VERSION 5.7 ;
BUSBITCHARS "[]" ;
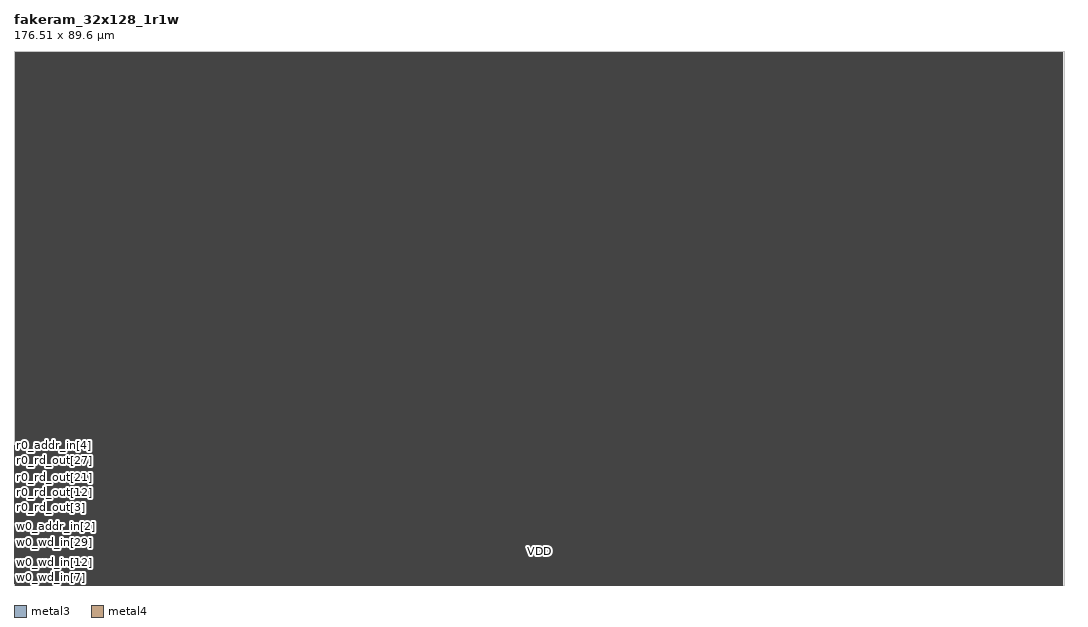
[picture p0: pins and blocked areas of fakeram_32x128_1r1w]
MACRO fakeram_32x128_1r1w
  FOREIGN fakeram_32x128_1r1w 0 0 ;
  SYMMETRY X Y R90 ;
  SIZE 176.510 BY 89.600 ;
  CLASS BLOCK ;
  PIN w0_wd_in[0]
    DIRECTION INPUT ;
    USE SIGNAL ;
    SHAPE ABUTMENT ;
    PORT
      LAYER metal3 ;
      RECT 0.000 0.280 0.140 0.420 ;
    END
  END w0_wd_in[0]
  PIN w0_wd_in[1]
    DIRECTION INPUT ;
    USE SIGNAL ;
    SHAPE ABUTMENT ;
    PORT
      LAYER metal3 ;
      RECT 0.000 0.560 0.140 0.700 ;
    END
  END w0_wd_in[1]
  PIN w0_wd_in[2]
    DIRECTION INPUT ;
    USE SIGNAL ;
    SHAPE ABUTMENT ;
    PORT
      LAYER metal3 ;
      RECT 0.000 0.840 0.140 0.980 ;
    END
  END w0_wd_in[2]
  PIN w0_wd_in[3]
    DIRECTION INPUT ;
    USE SIGNAL ;
    SHAPE ABUTMENT ;
    PORT
      LAYER metal3 ;
      RECT 0.000 1.120 0.140 1.260 ;
    END
  END w0_wd_in[3]
  PIN w0_wd_in[4]
    DIRECTION INPUT ;
    USE SIGNAL ;
    SHAPE ABUTMENT ;
    PORT
      LAYER metal3 ;
      RECT 0.000 1.400 0.140 1.540 ;
    END
  END w0_wd_in[4]
  PIN w0_wd_in[5]
    DIRECTION INPUT ;
    USE SIGNAL ;
    SHAPE ABUTMENT ;
    PORT
      LAYER metal3 ;
      RECT 0.000 1.680 0.140 1.820 ;
    END
  END w0_wd_in[5]
  PIN w0_wd_in[6]
    DIRECTION INPUT ;
    USE SIGNAL ;
    SHAPE ABUTMENT ;
    PORT
      LAYER metal3 ;
      RECT 0.000 1.960 0.140 2.100 ;
    END
  END w0_wd_in[6]
  PIN w0_wd_in[7]
    DIRECTION INPUT ;
    USE SIGNAL ;
    SHAPE ABUTMENT ;
    PORT
      LAYER metal3 ;
      RECT 0.000 2.240 0.140 2.380 ;
    END
  END w0_wd_in[7]
  PIN w0_wd_in[8]
    DIRECTION INPUT ;
    USE SIGNAL ;
    SHAPE ABUTMENT ;
    PORT
      LAYER metal3 ;
      RECT 0.000 2.520 0.140 2.660 ;
    END
  END w0_wd_in[8]
  PIN w0_wd_in[9]
    DIRECTION INPUT ;
    USE SIGNAL ;
    SHAPE ABUTMENT ;
    PORT
      LAYER metal3 ;
      RECT 0.000 2.800 0.140 2.940 ;
    END
  END w0_wd_in[9]
  PIN w0_wd_in[10]
    DIRECTION INPUT ;
    USE SIGNAL ;
    SHAPE ABUTMENT ;
    PORT
      LAYER metal3 ;
      RECT 0.000 3.080 0.140 3.220 ;
    END
  END w0_wd_in[10]
  PIN w0_wd_in[11]
    DIRECTION INPUT ;
    USE SIGNAL ;
    SHAPE ABUTMENT ;
    PORT
      LAYER metal3 ;
      RECT 0.000 3.360 0.140 3.500 ;
    END
  END w0_wd_in[11]
  PIN w0_wd_in[12]
    DIRECTION INPUT ;
    USE SIGNAL ;
    SHAPE ABUTMENT ;
    PORT
      LAYER metal3 ;
      RECT 0.000 3.640 0.140 3.780 ;
    END
  END w0_wd_in[12]
  PIN w0_wd_in[13]
    DIRECTION INPUT ;
    USE SIGNAL ;
    SHAPE ABUTMENT ;
    PORT
      LAYER metal3 ;
      RECT 0.000 3.920 0.140 4.060 ;
    END
  END w0_wd_in[13]
  PIN w0_wd_in[14]
    DIRECTION INPUT ;
    USE SIGNAL ;
    SHAPE ABUTMENT ;
    PORT
      LAYER metal3 ;
      RECT 0.000 4.200 0.140 4.340 ;
    END
  END w0_wd_in[14]
  PIN w0_wd_in[15]
    DIRECTION INPUT ;
    USE SIGNAL ;
    SHAPE ABUTMENT ;
    PORT
      LAYER metal3 ;
      RECT 0.000 4.480 0.140 4.620 ;
    END
  END w0_wd_in[15]
  PIN w0_wd_in[16]
    DIRECTION INPUT ;
    USE SIGNAL ;
    SHAPE ABUTMENT ;
    PORT
      LAYER metal3 ;
      RECT 0.000 4.760 0.140 4.900 ;
    END
  END w0_wd_in[16]
  PIN w0_wd_in[17]
    DIRECTION INPUT ;
    USE SIGNAL ;
    SHAPE ABUTMENT ;
    PORT
      LAYER metal3 ;
      RECT 0.000 5.040 0.140 5.180 ;
    END
  END w0_wd_in[17]
  PIN w0_wd_in[18]
    DIRECTION INPUT ;
    USE SIGNAL ;
    SHAPE ABUTMENT ;
    PORT
      LAYER metal3 ;
      RECT 0.000 5.320 0.140 5.460 ;
    END
  END w0_wd_in[18]
  PIN w0_wd_in[19]
    DIRECTION INPUT ;
    USE SIGNAL ;
    SHAPE ABUTMENT ;
    PORT
      LAYER metal3 ;
      RECT 0.000 5.600 0.140 5.740 ;
    END
  END w0_wd_in[19]
  PIN w0_wd_in[20]
    DIRECTION INPUT ;
    USE SIGNAL ;
    SHAPE ABUTMENT ;
    PORT
      LAYER metal3 ;
      RECT 0.000 5.880 0.140 6.020 ;
    END
  END w0_wd_in[20]
  PIN w0_wd_in[21]
    DIRECTION INPUT ;
    USE SIGNAL ;
    SHAPE ABUTMENT ;
    PORT
      LAYER metal3 ;
      RECT 0.000 6.160 0.140 6.300 ;
    END
  END w0_wd_in[21]
  PIN w0_wd_in[22]
    DIRECTION INPUT ;
    USE SIGNAL ;
    SHAPE ABUTMENT ;
    PORT
      LAYER metal3 ;
      RECT 0.000 6.440 0.140 6.580 ;
    END
  END w0_wd_in[22]
  PIN w0_wd_in[23]
    DIRECTION INPUT ;
    USE SIGNAL ;
    SHAPE ABUTMENT ;
    PORT
      LAYER metal3 ;
      RECT 0.000 6.720 0.140 6.860 ;
    END
  END w0_wd_in[23]
  PIN w0_wd_in[24]
    DIRECTION INPUT ;
    USE SIGNAL ;
    SHAPE ABUTMENT ;
    PORT
      LAYER metal3 ;
      RECT 0.000 7.000 0.140 7.140 ;
    END
  END w0_wd_in[24]
  PIN w0_wd_in[25]
    DIRECTION INPUT ;
    USE SIGNAL ;
    SHAPE ABUTMENT ;
    PORT
      LAYER metal3 ;
      RECT 0.000 7.280 0.140 7.420 ;
    END
  END w0_wd_in[25]
  PIN w0_wd_in[26]
    DIRECTION INPUT ;
    USE SIGNAL ;
    SHAPE ABUTMENT ;
    PORT
      LAYER metal3 ;
      RECT 0.000 7.560 0.140 7.700 ;
    END
  END w0_wd_in[26]
  PIN w0_wd_in[27]
    DIRECTION INPUT ;
    USE SIGNAL ;
    SHAPE ABUTMENT ;
    PORT
      LAYER metal3 ;
      RECT 0.000 7.840 0.140 7.980 ;
    END
  END w0_wd_in[27]
  PIN w0_wd_in[28]
    DIRECTION INPUT ;
    USE SIGNAL ;
    SHAPE ABUTMENT ;
    PORT
      LAYER metal3 ;
      RECT 0.000 8.120 0.140 8.260 ;
    END
  END w0_wd_in[28]
  PIN w0_wd_in[29]
    DIRECTION INPUT ;
    USE SIGNAL ;
    SHAPE ABUTMENT ;
    PORT
      LAYER metal3 ;
      RECT 0.000 8.400 0.140 8.540 ;
    END
  END w0_wd_in[29]
  PIN w0_wd_in[30]
    DIRECTION INPUT ;
    USE SIGNAL ;
    SHAPE ABUTMENT ;
    PORT
      LAYER metal3 ;
      RECT 0.000 8.680 0.140 8.820 ;
    END
  END w0_wd_in[30]
  PIN w0_wd_in[31]
    DIRECTION INPUT ;
    USE SIGNAL ;
    SHAPE ABUTMENT ;
    PORT
      LAYER metal3 ;
      RECT 0.000 8.960 0.140 9.100 ;
    END
  END w0_wd_in[31]
  PIN w0_addr_in[0]
    DIRECTION INPUT ;
    USE SIGNAL ;
    SHAPE ABUTMENT ;
    PORT
      LAYER metal3 ;
      RECT 0.000 9.240 0.140 9.380 ;
    END
  END w0_addr_in[0]
  PIN w0_addr_in[1]
    DIRECTION INPUT ;
    USE SIGNAL ;
    SHAPE ABUTMENT ;
    PORT
      LAYER metal3 ;
      RECT 0.000 9.520 0.140 9.660 ;
    END
  END w0_addr_in[1]
  PIN w0_addr_in[2]
    DIRECTION INPUT ;
    USE SIGNAL ;
    SHAPE ABUTMENT ;
    PORT
      LAYER metal3 ;
      RECT 0.000 9.800 0.140 9.940 ;
    END
  END w0_addr_in[2]
  PIN w0_addr_in[3]
    DIRECTION INPUT ;
    USE SIGNAL ;
    SHAPE ABUTMENT ;
    PORT
      LAYER metal3 ;
      RECT 0.000 10.080 0.140 10.220 ;
    END
  END w0_addr_in[3]
  PIN w0_addr_in[4]
    DIRECTION INPUT ;
    USE SIGNAL ;
    SHAPE ABUTMENT ;
    PORT
      LAYER metal3 ;
      RECT 0.000 10.360 0.140 10.500 ;
    END
  END w0_addr_in[4]
  PIN w0_addr_in[5]
    DIRECTION INPUT ;
    USE SIGNAL ;
    SHAPE ABUTMENT ;
    PORT
      LAYER metal3 ;
      RECT 0.000 10.640 0.140 10.780 ;
    END
  END w0_addr_in[5]
  PIN w0_addr_in[6]
    DIRECTION INPUT ;
    USE SIGNAL ;
    SHAPE ABUTMENT ;
    PORT
      LAYER metal3 ;
      RECT 0.000 10.920 0.140 11.060 ;
    END
  END w0_addr_in[6]
  PIN w0_clk
    DIRECTION INPUT ;
    USE SIGNAL ;
    SHAPE ABUTMENT ;
    PORT
      LAYER metal3 ;
      RECT 0.000 11.200 0.140 11.340 ;
    END
  END w0_clk
  PIN w0_ce_in
    DIRECTION INPUT ;
    USE SIGNAL ;
    SHAPE ABUTMENT ;
    PORT
      LAYER metal3 ;
      RECT 0.000 11.480 0.140 11.620 ;
    END
  END w0_ce_in
  PIN w0_we_in
    DIRECTION INPUT ;
    USE SIGNAL ;
    SHAPE ABUTMENT ;
    PORT
      LAYER metal3 ;
      RECT 0.000 11.760 0.140 11.900 ;
    END
  END w0_we_in
  PIN r0_rd_out[0]
    DIRECTION OUTPUT ;
    USE SIGNAL ;
    SHAPE ABUTMENT ;
    PORT
      LAYER metal3 ;
      RECT 0.000 12.040 0.140 12.180 ;
    END
  END r0_rd_out[0]
  PIN r0_rd_out[1]
    DIRECTION OUTPUT ;
    USE SIGNAL ;
    SHAPE ABUTMENT ;
    PORT
      LAYER metal3 ;
      RECT 0.000 12.320 0.140 12.460 ;
    END
  END r0_rd_out[1]
  PIN r0_rd_out[2]
    DIRECTION OUTPUT ;
    USE SIGNAL ;
    SHAPE ABUTMENT ;
    PORT
      LAYER metal3 ;
      RECT 0.000 12.600 0.140 12.740 ;
    END
  END r0_rd_out[2]
  PIN r0_rd_out[3]
    DIRECTION OUTPUT ;
    USE SIGNAL ;
    SHAPE ABUTMENT ;
    PORT
      LAYER metal3 ;
      RECT 0.000 12.880 0.140 13.020 ;
    END
  END r0_rd_out[3]
  PIN r0_rd_out[4]
    DIRECTION OUTPUT ;
    USE SIGNAL ;
    SHAPE ABUTMENT ;
    PORT
      LAYER metal3 ;
      RECT 0.000 13.160 0.140 13.300 ;
    END
  END r0_rd_out[4]
  PIN r0_rd_out[5]
    DIRECTION OUTPUT ;
    USE SIGNAL ;
    SHAPE ABUTMENT ;
    PORT
      LAYER metal3 ;
      RECT 0.000 13.440 0.140 13.580 ;
    END
  END r0_rd_out[5]
  PIN r0_rd_out[6]
    DIRECTION OUTPUT ;
    USE SIGNAL ;
    SHAPE ABUTMENT ;
    PORT
      LAYER metal3 ;
      RECT 0.000 13.720 0.140 13.860 ;
    END
  END r0_rd_out[6]
  PIN r0_rd_out[7]
    DIRECTION OUTPUT ;
    USE SIGNAL ;
    SHAPE ABUTMENT ;
    PORT
      LAYER metal3 ;
      RECT 0.000 14.000 0.140 14.140 ;
    END
  END r0_rd_out[7]
  PIN r0_rd_out[8]
    DIRECTION OUTPUT ;
    USE SIGNAL ;
    SHAPE ABUTMENT ;
    PORT
      LAYER metal3 ;
      RECT 0.000 14.280 0.140 14.420 ;
    END
  END r0_rd_out[8]
  PIN r0_rd_out[9]
    DIRECTION OUTPUT ;
    USE SIGNAL ;
    SHAPE ABUTMENT ;
    PORT
      LAYER metal3 ;
      RECT 0.000 14.560 0.140 14.700 ;
    END
  END r0_rd_out[9]
  PIN r0_rd_out[10]
    DIRECTION OUTPUT ;
    USE SIGNAL ;
    SHAPE ABUTMENT ;
    PORT
      LAYER metal3 ;
      RECT 0.000 14.840 0.140 14.980 ;
    END
  END r0_rd_out[10]
  PIN r0_rd_out[11]
    DIRECTION OUTPUT ;
    USE SIGNAL ;
    SHAPE ABUTMENT ;
    PORT
      LAYER metal3 ;
      RECT 0.000 15.120 0.140 15.260 ;
    END
  END r0_rd_out[11]
  PIN r0_rd_out[12]
    DIRECTION OUTPUT ;
    USE SIGNAL ;
    SHAPE ABUTMENT ;
    PORT
      LAYER metal3 ;
      RECT 0.000 15.400 0.140 15.540 ;
    END
  END r0_rd_out[12]
  PIN r0_rd_out[13]
    DIRECTION OUTPUT ;
    USE SIGNAL ;
    SHAPE ABUTMENT ;
    PORT
      LAYER metal3 ;
      RECT 0.000 15.680 0.140 15.820 ;
    END
  END r0_rd_out[13]
  PIN r0_rd_out[14]
    DIRECTION OUTPUT ;
    USE SIGNAL ;
    SHAPE ABUTMENT ;
    PORT
      LAYER metal3 ;
      RECT 0.000 15.960 0.140 16.100 ;
    END
  END r0_rd_out[14]
  PIN r0_rd_out[15]
    DIRECTION OUTPUT ;
    USE SIGNAL ;
    SHAPE ABUTMENT ;
    PORT
      LAYER metal3 ;
      RECT 0.000 16.240 0.140 16.380 ;
    END
  END r0_rd_out[15]
  PIN r0_rd_out[16]
    DIRECTION OUTPUT ;
    USE SIGNAL ;
    SHAPE ABUTMENT ;
    PORT
      LAYER metal3 ;
      RECT 0.000 16.520 0.140 16.660 ;
    END
  END r0_rd_out[16]
  PIN r0_rd_out[17]
    DIRECTION OUTPUT ;
    USE SIGNAL ;
    SHAPE ABUTMENT ;
    PORT
      LAYER metal3 ;
      RECT 0.000 16.800 0.140 16.940 ;
    END
  END r0_rd_out[17]
  PIN r0_rd_out[18]
    DIRECTION OUTPUT ;
    USE SIGNAL ;
    SHAPE ABUTMENT ;
    PORT
      LAYER metal3 ;
      RECT 0.000 17.080 0.140 17.220 ;
    END
  END r0_rd_out[18]
  PIN r0_rd_out[19]
    DIRECTION OUTPUT ;
    USE SIGNAL ;
    SHAPE ABUTMENT ;
    PORT
      LAYER metal3 ;
      RECT 0.000 17.360 0.140 17.500 ;
    END
  END r0_rd_out[19]
  PIN r0_rd_out[20]
    DIRECTION OUTPUT ;
    USE SIGNAL ;
    SHAPE ABUTMENT ;
    PORT
      LAYER metal3 ;
      RECT 0.000 17.640 0.140 17.780 ;
    END
  END r0_rd_out[20]
  PIN r0_rd_out[21]
    DIRECTION OUTPUT ;
    USE SIGNAL ;
    SHAPE ABUTMENT ;
    PORT
      LAYER metal3 ;
      RECT 0.000 17.920 0.140 18.060 ;
    END
  END r0_rd_out[21]
  PIN r0_rd_out[22]
    DIRECTION OUTPUT ;
    USE SIGNAL ;
    SHAPE ABUTMENT ;
    PORT
      LAYER metal3 ;
      RECT 0.000 18.200 0.140 18.340 ;
    END
  END r0_rd_out[22]
  PIN r0_rd_out[23]
    DIRECTION OUTPUT ;
    USE SIGNAL ;
    SHAPE ABUTMENT ;
    PORT
      LAYER metal3 ;
      RECT 0.000 18.480 0.140 18.620 ;
    END
  END r0_rd_out[23]
  PIN r0_rd_out[24]
    DIRECTION OUTPUT ;
    USE SIGNAL ;
    SHAPE ABUTMENT ;
    PORT
      LAYER metal3 ;
      RECT 0.000 18.760 0.140 18.900 ;
    END
  END r0_rd_out[24]
  PIN r0_rd_out[25]
    DIRECTION OUTPUT ;
    USE SIGNAL ;
    SHAPE ABUTMENT ;
    PORT
      LAYER metal3 ;
      RECT 0.000 19.040 0.140 19.180 ;
    END
  END r0_rd_out[25]
  PIN r0_rd_out[26]
    DIRECTION OUTPUT ;
    USE SIGNAL ;
    SHAPE ABUTMENT ;
    PORT
      LAYER metal3 ;
      RECT 0.000 19.320 0.140 19.460 ;
    END
  END r0_rd_out[26]
  PIN r0_rd_out[27]
    DIRECTION OUTPUT ;
    USE SIGNAL ;
    SHAPE ABUTMENT ;
    PORT
      LAYER metal3 ;
      RECT 0.000 19.600 0.140 19.740 ;
    END
  END r0_rd_out[27]
  PIN r0_rd_out[28]
    DIRECTION OUTPUT ;
    USE SIGNAL ;
    SHAPE ABUTMENT ;
    PORT
      LAYER metal3 ;
      RECT 0.000 19.880 0.140 20.020 ;
    END
  END r0_rd_out[28]
  PIN r0_rd_out[29]
    DIRECTION OUTPUT ;
    USE SIGNAL ;
    SHAPE ABUTMENT ;
    PORT
      LAYER metal3 ;
      RECT 0.000 20.160 0.140 20.300 ;
    END
  END r0_rd_out[29]
  PIN r0_rd_out[30]
    DIRECTION OUTPUT ;
    USE SIGNAL ;
    SHAPE ABUTMENT ;
    PORT
      LAYER metal3 ;
      RECT 0.000 20.440 0.140 20.580 ;
    END
  END r0_rd_out[30]
  PIN r0_rd_out[31]
    DIRECTION OUTPUT ;
    USE SIGNAL ;
    SHAPE ABUTMENT ;
    PORT
      LAYER metal3 ;
      RECT 0.000 20.720 0.140 20.860 ;
    END
  END r0_rd_out[31]
  PIN r0_addr_in[0]
    DIRECTION INPUT ;
    USE SIGNAL ;
    SHAPE ABUTMENT ;
    PORT
      LAYER metal3 ;
      RECT 0.000 21.000 0.140 21.140 ;
    END
  END r0_addr_in[0]
  PIN r0_addr_in[1]
    DIRECTION INPUT ;
    USE SIGNAL ;
    SHAPE ABUTMENT ;
    PORT
      LAYER metal3 ;
      RECT 0.000 21.280 0.140 21.420 ;
    END
  END r0_addr_in[1]
  PIN r0_addr_in[2]
    DIRECTION INPUT ;
    USE SIGNAL ;
    SHAPE ABUTMENT ;
    PORT
      LAYER metal3 ;
      RECT 0.000 21.560 0.140 21.700 ;
    END
  END r0_addr_in[2]
  PIN r0_addr_in[3]
    DIRECTION INPUT ;
    USE SIGNAL ;
    SHAPE ABUTMENT ;
    PORT
      LAYER metal3 ;
      RECT 0.000 21.840 0.140 21.980 ;
    END
  END r0_addr_in[3]
  PIN r0_addr_in[4]
    DIRECTION INPUT ;
    USE SIGNAL ;
    SHAPE ABUTMENT ;
    PORT
      LAYER metal3 ;
      RECT 0.000 22.120 0.140 22.260 ;
    END
  END r0_addr_in[4]
  PIN r0_addr_in[5]
    DIRECTION INPUT ;
    USE SIGNAL ;
    SHAPE ABUTMENT ;
    PORT
      LAYER metal3 ;
      RECT 0.000 22.400 0.140 22.540 ;
    END
  END r0_addr_in[5]
  PIN r0_addr_in[6]
    DIRECTION INPUT ;
    USE SIGNAL ;
    SHAPE ABUTMENT ;
    PORT
      LAYER metal3 ;
      RECT 0.000 22.680 0.140 22.820 ;
    END
  END r0_addr_in[6]
  PIN r0_clk
    DIRECTION INPUT ;
    USE SIGNAL ;
    SHAPE ABUTMENT ;
    PORT
      LAYER metal3 ;
      RECT 0.000 22.960 0.140 23.100 ;
    END
  END r0_clk
  PIN r0_ce_in
    DIRECTION INPUT ;
    USE SIGNAL ;
    SHAPE ABUTMENT ;
    PORT
      LAYER metal3 ;
      RECT 0.000 23.240 0.140 23.380 ;
    END
  END r0_ce_in
  PIN VDD
    DIRECTION INOUT ;
    USE POWER ;
    PORT
      LAYER metal4 ;
      RECT 0.190 0.000 176.320 0.140 ;
      RECT 0.190 0.560 176.320 0.700 ;
      RECT 0.190 1.120 176.320 1.260 ;
      RECT 0.190 1.680 176.320 1.820 ;
      RECT 0.190 2.240 176.320 2.380 ;
      RECT 0.190 2.800 176.320 2.940 ;
      RECT 0.190 3.360 176.320 3.500 ;
      RECT 0.190 3.920 176.320 4.060 ;
      RECT 0.190 4.480 176.320 4.620 ;
      RECT 0.190 5.040 176.320 5.180 ;
      RECT 0.190 5.600 176.320 5.740 ;
      RECT 0.190 6.160 176.320 6.300 ;
      RECT 0.190 6.720 176.320 6.860 ;
      RECT 0.190 7.280 176.320 7.420 ;
      RECT 0.190 7.840 176.320 7.980 ;
      RECT 0.190 8.400 176.320 8.540 ;
      RECT 0.190 8.960 176.320 9.100 ;
      RECT 0.190 9.520 176.320 9.660 ;
      RECT 0.190 10.080 176.320 10.220 ;
      RECT 0.190 10.640 176.320 10.780 ;
      RECT 0.190 11.200 176.320 11.340 ;
      RECT 0.190 11.760 176.320 11.900 ;
      RECT 0.190 12.320 176.320 12.460 ;
      RECT 0.190 12.880 176.320 13.020 ;
      RECT 0.190 13.440 176.320 13.580 ;
      RECT 0.190 14.000 176.320 14.140 ;
      RECT 0.190 14.560 176.320 14.700 ;
      RECT 0.190 15.120 176.320 15.260 ;
      RECT 0.190 15.680 176.320 15.820 ;
      RECT 0.190 16.240 176.320 16.380 ;
      RECT 0.190 16.800 176.320 16.940 ;
      RECT 0.190 17.360 176.320 17.500 ;
      RECT 0.190 17.920 176.320 18.060 ;
      RECT 0.190 18.480 176.320 18.620 ;
      RECT 0.190 19.040 176.320 19.180 ;
      RECT 0.190 19.600 176.320 19.740 ;
      RECT 0.190 20.160 176.320 20.300 ;
      RECT 0.190 20.720 176.320 20.860 ;
      RECT 0.190 21.280 176.320 21.420 ;
      RECT 0.190 21.840 176.320 21.980 ;
      RECT 0.190 22.400 176.320 22.540 ;
      RECT 0.190 22.960 176.320 23.100 ;
      RECT 0.190 23.520 176.320 23.660 ;
      RECT 0.190 24.080 176.320 24.220 ;
      RECT 0.190 24.640 176.320 24.780 ;
      RECT 0.190 25.200 176.320 25.340 ;
      RECT 0.190 25.760 176.320 25.900 ;
      RECT 0.190 26.320 176.320 26.460 ;
      RECT 0.190 26.880 176.320 27.020 ;
      RECT 0.190 27.440 176.320 27.580 ;
      RECT 0.190 28.000 176.320 28.140 ;
      RECT 0.190 28.560 176.320 28.700 ;
      RECT 0.190 29.120 176.320 29.260 ;
      RECT 0.190 29.680 176.320 29.820 ;
      RECT 0.190 30.240 176.320 30.380 ;
      RECT 0.190 30.800 176.320 30.940 ;
      RECT 0.190 31.360 176.320 31.500 ;
      RECT 0.190 31.920 176.320 32.060 ;
      RECT 0.190 32.480 176.320 32.620 ;
      RECT 0.190 33.040 176.320 33.180 ;
      RECT 0.190 33.600 176.320 33.740 ;
      RECT 0.190 34.160 176.320 34.300 ;
      RECT 0.190 34.720 176.320 34.860 ;
      RECT 0.190 35.280 176.320 35.420 ;
      RECT 0.190 35.840 176.320 35.980 ;
      RECT 0.190 36.400 176.320 36.540 ;
      RECT 0.190 36.960 176.320 37.100 ;
      RECT 0.190 37.520 176.320 37.660 ;
      RECT 0.190 38.080 176.320 38.220 ;
      RECT 0.190 38.640 176.320 38.780 ;
      RECT 0.190 39.200 176.320 39.340 ;
      RECT 0.190 39.760 176.320 39.900 ;
      RECT 0.190 40.320 176.320 40.460 ;
      RECT 0.190 40.880 176.320 41.020 ;
      RECT 0.190 41.440 176.320 41.580 ;
      RECT 0.190 42.000 176.320 42.140 ;
      RECT 0.190 42.560 176.320 42.700 ;
      RECT 0.190 43.120 176.320 43.260 ;
      RECT 0.190 43.680 176.320 43.820 ;
      RECT 0.190 44.240 176.320 44.380 ;
      RECT 0.190 44.800 176.320 44.940 ;
      RECT 0.190 45.360 176.320 45.500 ;
      RECT 0.190 45.920 176.320 46.060 ;
      RECT 0.190 46.480 176.320 46.620 ;
      RECT 0.190 47.040 176.320 47.180 ;
      RECT 0.190 47.600 176.320 47.740 ;
      RECT 0.190 48.160 176.320 48.300 ;
      RECT 0.190 48.720 176.320 48.860 ;
      RECT 0.190 49.280 176.320 49.420 ;
      RECT 0.190 49.840 176.320 49.980 ;
      RECT 0.190 50.400 176.320 50.540 ;
      RECT 0.190 50.960 176.320 51.100 ;
      RECT 0.190 51.520 176.320 51.660 ;
      RECT 0.190 52.080 176.320 52.220 ;
      RECT 0.190 52.640 176.320 52.780 ;
      RECT 0.190 53.200 176.320 53.340 ;
      RECT 0.190 53.760 176.320 53.900 ;
      RECT 0.190 54.320 176.320 54.460 ;
      RECT 0.190 54.880 176.320 55.020 ;
      RECT 0.190 55.440 176.320 55.580 ;
      RECT 0.190 56.000 176.320 56.140 ;
      RECT 0.190 56.560 176.320 56.700 ;
      RECT 0.190 57.120 176.320 57.260 ;
      RECT 0.190 57.680 176.320 57.820 ;
      RECT 0.190 58.240 176.320 58.380 ;
      RECT 0.190 58.800 176.320 58.940 ;
      RECT 0.190 59.360 176.320 59.500 ;
      RECT 0.190 59.920 176.320 60.060 ;
      RECT 0.190 60.480 176.320 60.620 ;
      RECT 0.190 61.040 176.320 61.180 ;
      RECT 0.190 61.600 176.320 61.740 ;
      RECT 0.190 62.160 176.320 62.300 ;
      RECT 0.190 62.720 176.320 62.860 ;
      RECT 0.190 63.280 176.320 63.420 ;
      RECT 0.190 63.840 176.320 63.980 ;
      RECT 0.190 64.400 176.320 64.540 ;
      RECT 0.190 64.960 176.320 65.100 ;
      RECT 0.190 65.520 176.320 65.660 ;
      RECT 0.190 66.080 176.320 66.220 ;
      RECT 0.190 66.640 176.320 66.780 ;
      RECT 0.190 67.200 176.320 67.340 ;
      RECT 0.190 67.760 176.320 67.900 ;
      RECT 0.190 68.320 176.320 68.460 ;
      RECT 0.190 68.880 176.320 69.020 ;
      RECT 0.190 69.440 176.320 69.580 ;
      RECT 0.190 70.000 176.320 70.140 ;
      RECT 0.190 70.560 176.320 70.700 ;
      RECT 0.190 71.120 176.320 71.260 ;
      RECT 0.190 71.680 176.320 71.820 ;
      RECT 0.190 72.240 176.320 72.380 ;
      RECT 0.190 72.800 176.320 72.940 ;
      RECT 0.190 73.360 176.320 73.500 ;
      RECT 0.190 73.920 176.320 74.060 ;
      RECT 0.190 74.480 176.320 74.620 ;
      RECT 0.190 75.040 176.320 75.180 ;
      RECT 0.190 75.600 176.320 75.740 ;
      RECT 0.190 76.160 176.320 76.300 ;
      RECT 0.190 76.720 176.320 76.860 ;
      RECT 0.190 77.280 176.320 77.420 ;
      RECT 0.190 77.840 176.320 77.980 ;
      RECT 0.190 78.400 176.320 78.540 ;
      RECT 0.190 78.960 176.320 79.100 ;
      RECT 0.190 79.520 176.320 79.660 ;
      RECT 0.190 80.080 176.320 80.220 ;
      RECT 0.190 80.640 176.320 80.780 ;
      RECT 0.190 81.200 176.320 81.340 ;
      RECT 0.190 81.760 176.320 81.900 ;
      RECT 0.190 82.320 176.320 82.460 ;
      RECT 0.190 82.880 176.320 83.020 ;
      RECT 0.190 83.440 176.320 83.580 ;
      RECT 0.190 84.000 176.320 84.140 ;
      RECT 0.190 84.560 176.320 84.700 ;
      RECT 0.190 85.120 176.320 85.260 ;
      RECT 0.190 85.680 176.320 85.820 ;
      RECT 0.190 86.240 176.320 86.380 ;
      RECT 0.190 86.800 176.320 86.940 ;
      RECT 0.190 87.360 176.320 87.500 ;
      RECT 0.190 87.920 176.320 88.060 ;
      RECT 0.190 88.480 176.320 88.620 ;
      RECT 0.190 89.040 176.320 89.180 ;
    END
  END VDD
  PIN VSS
    DIRECTION INOUT ;
    USE GROUND ;
    PORT
      LAYER metal4 ;
      RECT 0.190 0.280 176.320 0.420 ;
      RECT 0.190 0.840 176.320 0.980 ;
      RECT 0.190 1.400 176.320 1.540 ;
      RECT 0.190 1.960 176.320 2.100 ;
      RECT 0.190 2.520 176.320 2.660 ;
      RECT 0.190 3.080 176.320 3.220 ;
      RECT 0.190 3.640 176.320 3.780 ;
      RECT 0.190 4.200 176.320 4.340 ;
      RECT 0.190 4.760 176.320 4.900 ;
      RECT 0.190 5.320 176.320 5.460 ;
      RECT 0.190 5.880 176.320 6.020 ;
      RECT 0.190 6.440 176.320 6.580 ;
      RECT 0.190 7.000 176.320 7.140 ;
      RECT 0.190 7.560 176.320 7.700 ;
      RECT 0.190 8.120 176.320 8.260 ;
      RECT 0.190 8.680 176.320 8.820 ;
      RECT 0.190 9.240 176.320 9.380 ;
      RECT 0.190 9.800 176.320 9.940 ;
      RECT 0.190 10.360 176.320 10.500 ;
      RECT 0.190 10.920 176.320 11.060 ;
      RECT 0.190 11.480 176.320 11.620 ;
      RECT 0.190 12.040 176.320 12.180 ;
      RECT 0.190 12.600 176.320 12.740 ;
      RECT 0.190 13.160 176.320 13.300 ;
      RECT 0.190 13.720 176.320 13.860 ;
      RECT 0.190 14.280 176.320 14.420 ;
      RECT 0.190 14.840 176.320 14.980 ;
      RECT 0.190 15.400 176.320 15.540 ;
      RECT 0.190 15.960 176.320 16.100 ;
      RECT 0.190 16.520 176.320 16.660 ;
      RECT 0.190 17.080 176.320 17.220 ;
      RECT 0.190 17.640 176.320 17.780 ;
      RECT 0.190 18.200 176.320 18.340 ;
      RECT 0.190 18.760 176.320 18.900 ;
      RECT 0.190 19.320 176.320 19.460 ;
      RECT 0.190 19.880 176.320 20.020 ;
      RECT 0.190 20.440 176.320 20.580 ;
      RECT 0.190 21.000 176.320 21.140 ;
      RECT 0.190 21.560 176.320 21.700 ;
      RECT 0.190 22.120 176.320 22.260 ;
      RECT 0.190 22.680 176.320 22.820 ;
      RECT 0.190 23.240 176.320 23.380 ;
      RECT 0.190 23.800 176.320 23.940 ;
      RECT 0.190 24.360 176.320 24.500 ;
      RECT 0.190 24.920 176.320 25.060 ;
      RECT 0.190 25.480 176.320 25.620 ;
      RECT 0.190 26.040 176.320 26.180 ;
      RECT 0.190 26.600 176.320 26.740 ;
      RECT 0.190 27.160 176.320 27.300 ;
      RECT 0.190 27.720 176.320 27.860 ;
      RECT 0.190 28.280 176.320 28.420 ;
      RECT 0.190 28.840 176.320 28.980 ;
      RECT 0.190 29.400 176.320 29.540 ;
      RECT 0.190 29.960 176.320 30.100 ;
      RECT 0.190 30.520 176.320 30.660 ;
      RECT 0.190 31.080 176.320 31.220 ;
      RECT 0.190 31.640 176.320 31.780 ;
      RECT 0.190 32.200 176.320 32.340 ;
      RECT 0.190 32.760 176.320 32.900 ;
      RECT 0.190 33.320 176.320 33.460 ;
      RECT 0.190 33.880 176.320 34.020 ;
      RECT 0.190 34.440 176.320 34.580 ;
      RECT 0.190 35.000 176.320 35.140 ;
      RECT 0.190 35.560 176.320 35.700 ;
      RECT 0.190 36.120 176.320 36.260 ;
      RECT 0.190 36.680 176.320 36.820 ;
      RECT 0.190 37.240 176.320 37.380 ;
      RECT 0.190 37.800 176.320 37.940 ;
      RECT 0.190 38.360 176.320 38.500 ;
      RECT 0.190 38.920 176.320 39.060 ;
      RECT 0.190 39.480 176.320 39.620 ;
      RECT 0.190 40.040 176.320 40.180 ;
      RECT 0.190 40.600 176.320 40.740 ;
      RECT 0.190 41.160 176.320 41.300 ;
      RECT 0.190 41.720 176.320 41.860 ;
      RECT 0.190 42.280 176.320 42.420 ;
      RECT 0.190 42.840 176.320 42.980 ;
      RECT 0.190 43.400 176.320 43.540 ;
      RECT 0.190 43.960 176.320 44.100 ;
      RECT 0.190 44.520 176.320 44.660 ;
      RECT 0.190 45.080 176.320 45.220 ;
      RECT 0.190 45.640 176.320 45.780 ;
      RECT 0.190 46.200 176.320 46.340 ;
      RECT 0.190 46.760 176.320 46.900 ;
      RECT 0.190 47.320 176.320 47.460 ;
      RECT 0.190 47.880 176.320 48.020 ;
      RECT 0.190 48.440 176.320 48.580 ;
      RECT 0.190 49.000 176.320 49.140 ;
      RECT 0.190 49.560 176.320 49.700 ;
      RECT 0.190 50.120 176.320 50.260 ;
      RECT 0.190 50.680 176.320 50.820 ;
      RECT 0.190 51.240 176.320 51.380 ;
      RECT 0.190 51.800 176.320 51.940 ;
      RECT 0.190 52.360 176.320 52.500 ;
      RECT 0.190 52.920 176.320 53.060 ;
      RECT 0.190 53.480 176.320 53.620 ;
      RECT 0.190 54.040 176.320 54.180 ;
      RECT 0.190 54.600 176.320 54.740 ;
      RECT 0.190 55.160 176.320 55.300 ;
      RECT 0.190 55.720 176.320 55.860 ;
      RECT 0.190 56.280 176.320 56.420 ;
      RECT 0.190 56.840 176.320 56.980 ;
      RECT 0.190 57.400 176.320 57.540 ;
      RECT 0.190 57.960 176.320 58.100 ;
      RECT 0.190 58.520 176.320 58.660 ;
      RECT 0.190 59.080 176.320 59.220 ;
      RECT 0.190 59.640 176.320 59.780 ;
      RECT 0.190 60.200 176.320 60.340 ;
      RECT 0.190 60.760 176.320 60.900 ;
      RECT 0.190 61.320 176.320 61.460 ;
      RECT 0.190 61.880 176.320 62.020 ;
      RECT 0.190 62.440 176.320 62.580 ;
      RECT 0.190 63.000 176.320 63.140 ;
      RECT 0.190 63.560 176.320 63.700 ;
      RECT 0.190 64.120 176.320 64.260 ;
      RECT 0.190 64.680 176.320 64.820 ;
      RECT 0.190 65.240 176.320 65.380 ;
      RECT 0.190 65.800 176.320 65.940 ;
      RECT 0.190 66.360 176.320 66.500 ;
      RECT 0.190 66.920 176.320 67.060 ;
      RECT 0.190 67.480 176.320 67.620 ;
      RECT 0.190 68.040 176.320 68.180 ;
      RECT 0.190 68.600 176.320 68.740 ;
      RECT 0.190 69.160 176.320 69.300 ;
      RECT 0.190 69.720 176.320 69.860 ;
      RECT 0.190 70.280 176.320 70.420 ;
      RECT 0.190 70.840 176.320 70.980 ;
      RECT 0.190 71.400 176.320 71.540 ;
      RECT 0.190 71.960 176.320 72.100 ;
      RECT 0.190 72.520 176.320 72.660 ;
      RECT 0.190 73.080 176.320 73.220 ;
      RECT 0.190 73.640 176.320 73.780 ;
      RECT 0.190 74.200 176.320 74.340 ;
      RECT 0.190 74.760 176.320 74.900 ;
      RECT 0.190 75.320 176.320 75.460 ;
      RECT 0.190 75.880 176.320 76.020 ;
      RECT 0.190 76.440 176.320 76.580 ;
      RECT 0.190 77.000 176.320 77.140 ;
      RECT 0.190 77.560 176.320 77.700 ;
      RECT 0.190 78.120 176.320 78.260 ;
      RECT 0.190 78.680 176.320 78.820 ;
      RECT 0.190 79.240 176.320 79.380 ;
      RECT 0.190 79.800 176.320 79.940 ;
      RECT 0.190 80.360 176.320 80.500 ;
      RECT 0.190 80.920 176.320 81.060 ;
      RECT 0.190 81.480 176.320 81.620 ;
      RECT 0.190 82.040 176.320 82.180 ;
      RECT 0.190 82.600 176.320 82.740 ;
      RECT 0.190 83.160 176.320 83.300 ;
      RECT 0.190 83.720 176.320 83.860 ;
      RECT 0.190 84.280 176.320 84.420 ;
      RECT 0.190 84.840 176.320 84.980 ;
      RECT 0.190 85.400 176.320 85.540 ;
      RECT 0.190 85.960 176.320 86.100 ;
      RECT 0.190 86.520 176.320 86.660 ;
      RECT 0.190 87.080 176.320 87.220 ;
      RECT 0.190 87.640 176.320 87.780 ;
      RECT 0.190 88.200 176.320 88.340 ;
      RECT 0.190 88.760 176.320 88.900 ;
      RECT 0.190 89.320 176.320 89.460 ;
    END
  END VSS
  OBS
    LAYER metal1 ;
      RECT 0.000 0.000 176.510 89.600 ;
    LAYER metal2 ;
      RECT 0.000 0.000 176.510 89.600 ;
    LAYER metal3 ;
      RECT 0.000 0.000 176.510 89.600 ;
  END
END fakeram_32x128_1r1w
END LIBRARY
